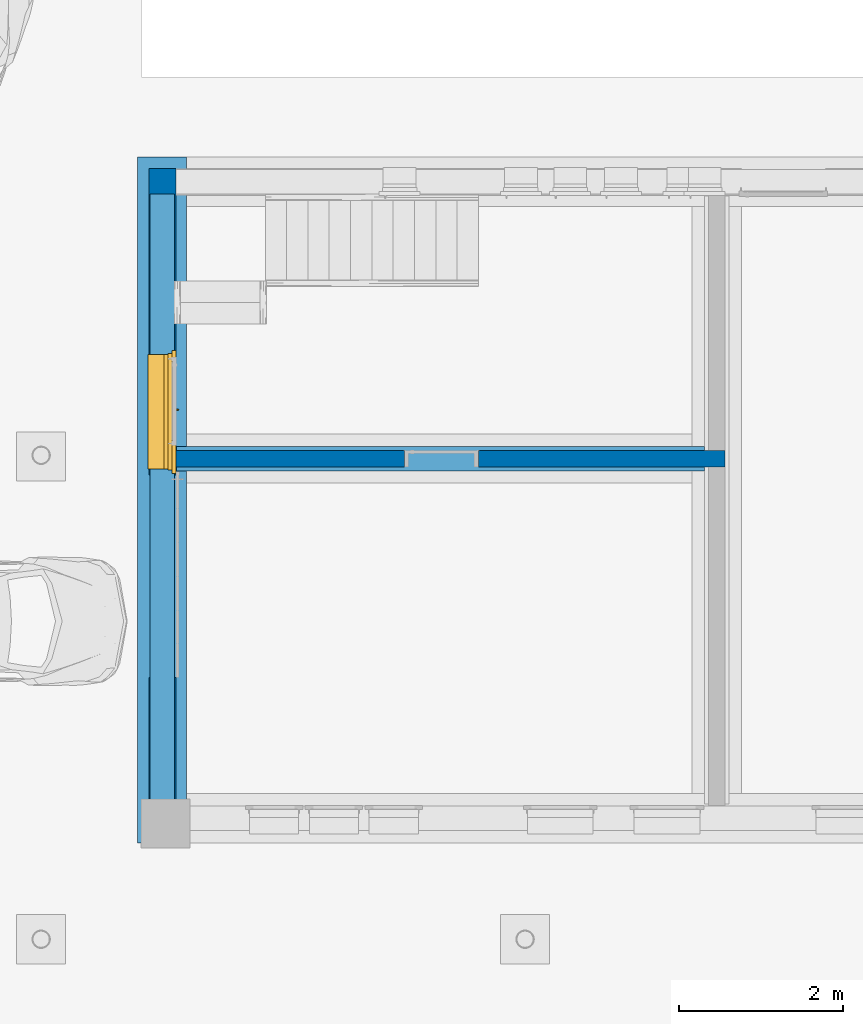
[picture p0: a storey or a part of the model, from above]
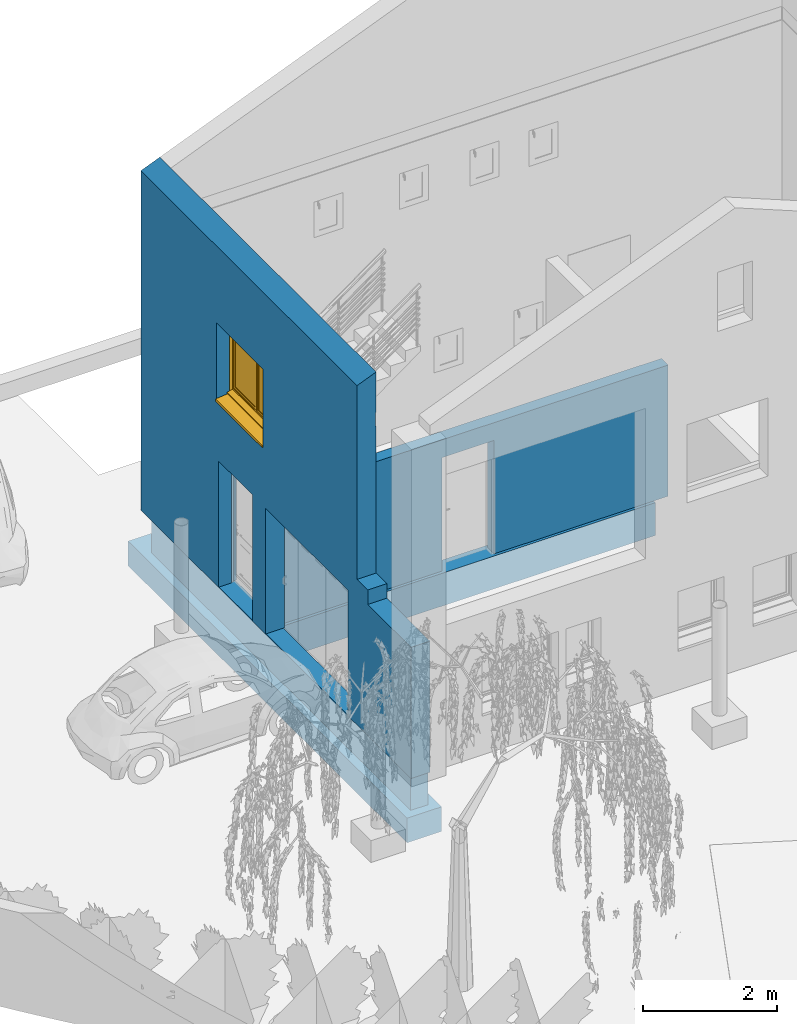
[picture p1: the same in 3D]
Properties of the parts of a building model (IFC2X3)

# File
Description: ViewDefinition [CoordinationView_V2.0, QuantityTakeOffAddOnView]
File name: Numéro du projet
Time: 2022-11-21T19:39:14
Written by: The EXPRESS Data Manager Version 5.02.0100.07 : 28 Aug 2013
Made in: 22.0.2.392 - Exporter 22.0.2.392 - Interface utilisateur alternative 22.0.2.392
Comment: STEP Physical File produced by: The EXPRESS Data Manager Version 5.02.0100.07 : 28 Aug 2013 * Module: EDMstepFileFactory/EDMstandAlone * Creation date: Mon Nov 21 19:39:14 2022 * Host: DESKTOP-0GH62VQ * Database: C:\Users\PC-PAT~1\AppData\Local\Temp\c2ba28db-b95e-4a9b-a4a2-2ccf43ad36bc\0f3ee18b-cbed-4b06-b284-a12b78713adf\ifc * Database version: 5507 * Database creation date: Mon Nov 21 19:39:06 2022 * Schema: IFC2X3 * Model: DataRepository.ifc * Model creation date: Mon Nov 21 19:39:07 2022 * Header model: DataRepository.ifc_HeaderModel * Header model creation date: Mon Nov 21 19:39:07 2022 * EDMuser: sdai-user * EDMgroup: sdai-group * License ID and type: 5605 : Permanent license. Expiry date: * EDMstepFileFactory options: 020000

# IfcProject, Numéro du projet
LongName: Nom du projet; Phase: Etat du projet

# IfcSite, Surface:269051
RefLatitude: 48, 51, 23, 999633; RefLongitude: 2, 21, 3, 553905; RefElevation: 0 m

# IfcSite: Boîte à lettres - Personnelle:26 x 33 x 38.5, Boîte à lettres - Personnelle:26 x 33 x 38.5:391761
Material: Métal - Chrome, Polycarbonate - Clair, Métal - Alu brossé, Aluminium laqué - Gris

# IfcSite: Portail métal - Double:3000mm x 1100mm 2, Portail métal - Double:3000mm x 1100mm 2:387421
Material: Peinture - Or, Portail - Chapeaux piliers, Peinture - Noir, Portail - Couleur, Portail - Piliers

# IfcBuilding
Pset_BuildingCommon - NumberOfStoreys: 3

# IfcBuildingStorey: Niveau:Ligne du Niveau (3)
Name | LongName | Elevation (m)
Niveau rdc | Niveau rdc | -1.94916e-14
Niveau étage | Niveau étage | 2.65
Niveau comble | Niveau comble | 5.6

# IfcSpace: Ch1 3:344937, 3
In: Niveau étage
LongName: Ch1; InteriorOrExteriorSpace: INTERNAL
Pset_SpaceCommon - Reference: Ch1 3
BaseQuantities - NetFloorArea: 9.82818 m2; Height: 2.4384 m; GrossPerimeter: 12.88 m; GrossFloorArea: 9.82818 m2; GrossVolume: 23.965 m3

# IfcSpace: Ch2 7:344949, 7
In: Niveau étage
LongName: Ch2; InteriorOrExteriorSpace: INTERNAL
Pset_SpaceCommon - Reference: Ch2 7
BaseQuantities - NetFloorArea: 11.398 m2; Height: 2.4384 m; GrossPerimeter: 13.51 m; GrossFloorArea: 11.398 m2; GrossVolume: 27.7929 m3

# IfcSpace: Cuisine 6:344946, 6
In: Niveau étage
LongName: Cuisine; InteriorOrExteriorSpace: INTERNAL
Pset_SpaceCommon - Reference: Cuisine 6
BaseQuantities - NetFloorArea: 9.671 m2; Height: 2.4384 m; GrossPerimeter: 12.46 m; GrossFloorArea: 9.671 m2; GrossVolume: 23.5818 m3

# IfcSpace: Dgt 4:344940, 4
In: Niveau étage
LongName: Dgt; InteriorOrExteriorSpace: INTERNAL
Pset_SpaceCommon - Reference: Dgt 4
BaseQuantities - NetFloorArea: 8.32768 m2; Height: 2.4384 m; GrossPerimeter: 13.481 m; GrossFloorArea: 8.32768 m2; GrossVolume: 20.3062 m3

# IfcSpace: Entrée 16:398265, 16
In: Niveau rdc
LongName: Entrée; InteriorOrExteriorSpace: INTERNAL
Pset_SpaceCommon - Reference: Entrée 16
BaseQuantities - NetFloorArea: 20.1594 m2; Height: 2.4384 m; GrossPerimeter: 19.1951 m; GrossFloorArea: 20.1594 m2; GrossVolume: 49.1568 m3

# IfcSpace: Garage 8:344957, 8
In: Niveau rdc
LongName: Garage; InteriorOrExteriorSpace: INTERNAL
Pset_SpaceCommon - Reference: Garage 8
BaseQuantities - NetFloorArea: 26.8007 m2; Height: 2.4384 m; GrossPerimeter: 21.2451 m; GrossFloorArea: 26.8007 m2; GrossVolume: 65.3509 m3

# IfcSpace: Pièce 10:345585, 10
In: Niveau comble
LongName: Pièce; InteriorOrExteriorSpace: INTERNAL
Pset_SpaceCommon - Reference: Pièce 10
BaseQuantities - NetFloorArea: 16.624 m2; Height: 2.4384 m; GrossPerimeter: 16.7226 m; GrossFloorArea: 16.624 m2; GrossVolume: 40.5359 m3

# IfcSpace: Pièce 9:345581, 9
In: Niveau comble
LongName: Pièce; InteriorOrExteriorSpace: INTERNAL
Pset_SpaceCommon - Reference: Pièce 9
BaseQuantities - NetFloorArea: 17.0934 m2; Height: 2.4384 m; GrossPerimeter: 16.69 m; GrossFloorArea: 17.0934 m2; GrossVolume: 41.6804 m3

# IfcSpace: Salon 5:344943, 5
In: Niveau étage
LongName: Salon; InteriorOrExteriorSpace: INTERNAL
Pset_SpaceCommon - Reference: Salon 5
BaseQuantities - NetFloorArea: 24.1371 m2; Height: 2.4384 m; GrossPerimeter: 28.9033 m; GrossFloorArea: 24.1371 m2; GrossVolume: 58.856 m3

# IfcSpace: SdB 1:344931, 1
In: Niveau étage
LongName: SdB; InteriorOrExteriorSpace: INTERNAL
Pset_SpaceCommon - Reference: SdB 1
BaseQuantities - NetFloorArea: 3.70925 m2; Height: 2.4384 m; GrossPerimeter: 7.71 m; GrossFloorArea: 3.70925 m2; GrossVolume: 9.04464 m3

# IfcSpace: Studio 15:396011, 15
In: Niveau rdc
LongName: Studio; InteriorOrExteriorSpace: INTERNAL
Pset_SpaceCommon - Reference: Studio 15
BaseQuantities - NetFloorArea: 28.8287 m2; Height: 2.4384 m; GrossPerimeter: 22.6249 m; GrossFloorArea: 28.8287 m2; GrossVolume: 70.2958 m3

# IfcSpace: Wc 2:344934, 2
In: Niveau étage
LongName: Wc; InteriorOrExteriorSpace: INTERNAL
Pset_SpaceCommon - Reference: Wc 2
BaseQuantities - NetFloorArea: 1.90475 m2; Height: 2.4384 m; GrossPerimeter: 5.91 m; GrossFloorArea: 1.90475 m2; GrossVolume: 4.64454 m3

# IfcBeam: IPE-Poutrelles:IPE200 (2)
In: Niveau étage
Type - Pset_BeamCommon - IsExternal: no; LoadBearing: yes
Material: Métal - Acier - 345 MPa
BaseQuantities - GrossSurfaceArea: 0 m2
Pset_BeamCommon - Reference: IPE200
Pset_QuantityTakeOff - Reference: IPE200; sets with these values: 2
Name (IPE-Poutrelles:IPE200:...) | NetVolume (m3) | Slope (deg) | Span (m) | NetSurfaceArea (m2)
289930 | 0.0223025 | 0 | 8.185 | 6.29341
290069 | 0.0241417 | 0.51735 | 8.86 | 6.81194

# IfcBeam: IPE-Poutrelles:IPE80 (29)
In: Niveau étage
Type - Pset_BeamCommon - IsExternal: no; LoadBearing: yes
BaseQuantities - GrossSurfaceArea: 0 m2
Pset_BeamCommon - Reference: IPE80; Slope: 0 deg
Pset_QuantityTakeOff - Reference: IPE80; sets with these values: 2
Name (IPE-Poutrelles:IPE80:...) | Material | NetVolume (m3) | Span (m) | NetSurfaceArea (m2)
288680 | Métal - Acier - 345 MPa | 0.00150805 | 2.03 | 0.666997
288683 | Métal - Acier - 345 MPa | 0.00150805 | 2.03 | 0.666997
288686 | Métal - Acier - 345 MPa | 0.00150805 | 2.03 | 0.666997
288689 | Métal - Acier - 345 MPa | 0.00150805 | 2.03 | 0.666997
288692 | Métal - Acier - 345 MPa | 0.00150805 | 2.03 | 0.666997
288695 | Métal - Acier - 345 MPa | 0.00150805 | 2.03 | 0.666997
288698 | Métal - Acier - 345 MPa | 0.00150805 | 2.03 | 0.666997
288701 | Métal - Acier - 345 MPa | 0.00150805 | 2.03 | 0.666997
288704 | Métal - Acier - 345 MPa | 0.00150805 | 2.03 | 0.666997
288707 | Métal - Acier - 345 MPa | 0.00150805 | 2.03 | 0.666997
288710 | Métal - Acier - 345 MPa | 0.00140924 | 1.91 | 0.623397
288713 | Métal - Acier - 345 MPa | 0.00114552 | 1.61 | 0.507021
288716 | Métal - Acier - 345 MPa | 0.000719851 | 1.037 | 0.319184
290215 | Peinture - Noir | 0.00142262 | 1.915 | 0.629298
290218 | Métal - Acier - 345 MPa | 0.00142262 | 1.915 | 0.629298
290221 | Métal - Acier - 345 MPa | 0.00142262 | 1.915 | 0.629298
290224 | Métal - Acier - 345 MPa | 0.00142262 | 1.915 | 0.629298
290227 | Métal - Acier - 345 MPa | 0.00142262 | 1.915 | 0.629298
290230 | Métal - Acier - 345 MPa | 0.00142262 | 1.915 | 0.629298
290233 | Métal - Acier - 345 MPa | 0.00142262 | 1.915 | 0.629298
290236 | Métal - Acier - 345 MPa | 0.00142262 | 1.915 | 0.629298
290239 | Métal - Acier - 345 MPa | 0.00142262 | 1.915 | 0.629298
290242 | Métal - Acier - 345 MPa | 0.00142262 | 1.915 | 0.629298
290245 | Métal - Acier - 345 MPa | 0.00133496 | 1.915 | 0.590616
363687 | Métal - Acier - 345 MPa | 0.00133496 | 1.812 | 0.590616
363748 | Métal - Acier - 345 MPa | 0.000941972 | 1.337 | 0.417199
364011 | Métal - Acier - 345 MPa | 0.001982 | 2.704 | 0.876142
364347 | Métal - Acier - 345 MPa | 0.000514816 | 0.762 | 0.228707
364498 | Peinture - Noir | 0.00134461 | 1.81 | 0.594876

# IfcBuildingElementProxy: Arbre 3D - Saule pleureur:Saule pleureur - 6 m, Arbre 3D - Saule pleureur:Saule pleureur - 6 m:264246
In: Niveau rdc
Type - Material: <Unnamed>
Pset_BuildingElementProxyCommon - Reference: Saule pleureur - 6 m; sets with these values: 2

# IfcBuildingElementProxy: Kitchenette - Moyenne:1372 mm, Kitchenette - Moyenne:1372 mm:354255
In: 6
Type - Material: Bois - Mélaminé blanc, Plastique - Noir, Métal - Chrome
Material: Métal - Chrome, Métal - Acier, Poli, <Unnamed>, Métal - Finition peinture - Ivoire, Mat, Peinture - Ivoire, Plastique - Noir, Bois - Mélaminé blanc, Bois - Mélaminé hêtre
Pset_BuildingElementProxyCommon - Reference: 1372 mm; sets with these values: 2

# IfcBuildingElementProxy: Meuble TV:1470 x 500 x 560 mm, Meuble TV:1470 x 500 x 560 mm:340517
In: Niveau comble
Type - Material: Bois - Mélaminé rouge, Verre - Meuble TV
Material: Verre - Meuble TV, Bois - Mélaminé rouge, Bois - Mélaminé gris
Pset_BuildingElementProxyCommon - Reference: 1470 x 500 x 560 mm; sets with these values: 2

# IfcBuildingElementProxy: Meuble TV:Meuble TV, Meuble TV:Meuble TV:354305
In: 5
Type - Material: Bois - Mélaminé rouge, Verre - Meuble TV
Material: Verre - Meuble TV, Bois - Mélaminé rouge, Bois - Mélaminé gris
Pset_BuildingElementProxyCommon - Reference: Meuble TV; sets with these values: 2

# IfcBuildingElementProxy: RPC Arbre - Feuilles caduques:Cerisier japonais - 4.5 mètres, RPC Arbre - Feuilles caduques:Cerisier japonais - 4.5 mètres:331745
In: Niveau comble
Type - Material: <Unnamed>
Pset_BuildingElementProxyCommon - Reference: Cerisier japonais - 4.5 mètres; sets with these values: 2

# IfcBuildingElementProxy: RPC Arbuste:Laurier-rose - 1.62 mètres (21)
In: Niveau rdc
Type - Material: <Unnamed>
Pset_BuildingElementProxyCommon - Reference: Laurier-rose - 1.62 mètres; sets with these values: 2
Name (RPC Arbuste:Laurier-rose - 1.62 mètres:...)
265842
265873
265898
265975
266002
266037
266072
266119
266152
266185
266230
266255
266351
266424
266471
266728
266797
266842
266947
266998
267203

# IfcBuildingElementProxy: RPC Coccinelle:RPC Coccinelle (3)
In: Niveau rdc
Type - Material: <Unnamed>
Pset_BuildingElementProxyCommon - Reference: RPC Coccinelle; sets with these values: 2
Name (RPC Coccinelle:RPC Coccinelle:...)
281773
281916
282133

# IfcBuildingElementProxy: RPC Femme:Lisa, RPC Femme:Lisa:361304
In: Niveau étage
Type - Material: <Unnamed>
Pset_BuildingElementProxyCommon - Reference: Lisa; sets with these values: 2

# IfcBuildingElementProxy: TV - Ecran plat:810 mm, TV - Ecran plat:810 mm:355405
In: 5
Type - Material: TV - Cadre
Material: TV - Cadre, TV - Noir, TV - Verre
Pset_BuildingElementProxyCommon - Reference: 810 mm; sets with these values: 2

# IfcColumn: Poteau béton - Carré:600mm x 600mm (4)
In: Niveau rdc
Type - PredefinedType: COLUMN; Material: Maçonnerie - Béton coulé sur place
Type - Pset_ColumnCommon - IsExternal: no; LoadBearing: yes
BaseQuantities - CrossSectionArea: 0.36 m2
Pset_ColumnCommon - Reference: 600mm x 600mm
Pset_QuantityTakeOff - Reference: 600mm x 600mm; sets with these values: 2
Name (Poteau béton - Carré:600mm x 600mm:...) | Length (m) | OuterSurfaceArea (m2) | GrossVolume (m3) = NetVolume (m3)
238808 | 6.16673 | 14.8002 | 2.22002
286273 | 0.4 | 0.96 | 0.144
286579 | 0.4 | 0.96 | 0.144
290105 | 0.4 | 0.96 | 0.144

# IfcColumn: Profil creux circulaire PCC:219.1x8CHS, Profil creux circulaire PCC:219.1x8CHS:316609
In: Niveau étage
Type - PredefinedType: COLUMN; Material: Métal - Acier
Type - Pset_ColumnCommon - IsExternal: no; LoadBearing: yes
BaseQuantities - Length: 5.95 m; CrossSectionArea: 0.00530481 m2; OuterSurfaceArea: 7.89196 m2; GrossVolume: 0.0315636 m3; NetVolume: 0.0315734 m3
Pset_ColumnCommon - Reference: 219.1x8CHS
Pset_QuantityTakeOff - Reference: 219.1x8CHS; sets with these values: 2

# IfcColumn: Profil creux circulaire PCC:219.1x8CHS (3)
In: Niveau rdc
Type - PredefinedType: COLUMN; Material: Peinture - Noir
Type - Pset_ColumnCommon - IsExternal: no; LoadBearing: yes
BaseQuantities - Length: 1.97 m; CrossSectionArea: 0.00530481 m2; OuterSurfaceArea: 2.61297 m2; GrossVolume: 0.0104505 m3; NetVolume: 0.0104537 m3
Pset_ColumnCommon - Reference: 219.1x8CHS
Pset_QuantityTakeOff - Reference: 219.1x8CHS; sets with these values: 2
Name (Profil creux circulaire PCC:219.1x8CHS:...)
287799
287893
290107

# IfcDoor: Entrée (avec angle d'ouverture):PP Avec moulures (0.90 m x 2.15 m), Entrée (avec angle d'ouverture):PP Avec moulures (0.90 m x 2.15 m):258819
In: Niveau rdc
Type - OperationType: SINGLE_SWING_LEFT; ParameterTakesPrecedence: no; Sizeable: no; Material: Porte d'entrée - Poignée, Porte d'entrée - Panneau, Peinture - Noir, Porte d'entrée - Cadre
Type - Entrée (avec angle d'ouverture):PP Avec moulures (0.90 m x 2.15 m):258819:1 - PanelOperation: SWINGING
Type - Pset_DoorCommon - IsExternal: yes; ThermalTransmittance: 5.5617 kg/K/s3
OverallHeight: 2.34 m; OverallWidth: 1.08 m; Material: Porte d'entrée - Poignée, Porte d'entrée - Panneau, Porte d'entrée - Cadre
Pset_DoorCommon - Reference: PP Avec moulures (0.90 m x 2.15 m)
Pset_QuantityTakeOff - Reference: PP Avec moulures (0.90 m x 2.15 m)
BaseQuantities - Height: 2.3 m; Width: 1 m; Area: 2.3 m2

# IfcDoor: Entrée (avec angle d'ouverture):PP Avec moulures (0.90 m x 2.15 m), Entrée (avec angle d'ouverture):PP Avec moulures (0.90 m x 2.15 m):302061
In: Niveau rdc
Type - OperationType: SINGLE_SWING_RIGHT; ParameterTakesPrecedence: no; Sizeable: no; Material: Porte d'entrée - Poignée, Porte d'entrée - Panneau, Porte d'entrée - Cadre, Peinture - Noir
Type - Entrée (avec angle d'ouverture):PP Avec moulures (0.90 m x 2.15 m):302061:1 - PanelOperation: SWINGING
Type - Pset_DoorCommon - IsExternal: yes; ThermalTransmittance: 5.5617 kg/K/s3
OverallHeight: 2.34 m; OverallWidth: 1.08 m; Material: Porte d'entrée - Poignée, Porte d'entrée - Panneau, Porte d'entrée - Cadre
Pset_DoorCommon - Reference: PP Avec moulures (0.90 m x 2.15 m)
Pset_QuantityTakeOff - Reference: PP Avec moulures (0.90 m x 2.15 m)
BaseQuantities - Height: 2.3 m; Width: 1 m; Area: 2.3 m2

# IfcDoor: Garage coulissante:Garage coulissante, Garage coulissante:Garage coulissante:237741
In: Niveau rdc
Type - OperationType: SLIDING_TO_LEFT; ParameterTakesPrecedence: no; Sizeable: no; Material: Peinture - Grise, Plastique - Noir
Type - Garage coulissante:Garage coulissante:237741:1 - PanelOperation: SLIDING
Type - Pset_DoorCommon - IsExternal: yes; ThermalTransmittance: 3.7021 kg/K/s3
OverallHeight: 2.3 m; OverallWidth: 2.47 m; Material: Peinture - Grise, Verre, Plastique - Noir
Pset_DoorCommon - Reference: Garage coulissante
Pset_QuantityTakeOff - Reference: Garage coulissante
BaseQuantities - Height: 2.3 m; Width: 2.47 m; Area: 5.681 m2

# IfcDoor: Int. Double vitrée:Cintré 2x4 - 1.46 m x 2.04 m, Int. Double vitrée:Cintré 2x4 - 1.46 m x 2.04 m:275557
In: Niveau étage
Type - OperationType: DOUBLE_DOOR_SINGLE_SWING; ParameterTakesPrecedence: no; Sizeable: no; Material: Porte - Poignée, Porte - Panneau, Porte - Cadre, Verre
Type - Int. Double vitrée:Cintré 2x4 - 1.46 m x 2.04 m:275557:1 - PanelOperation: SWINGING
Type - Pset_DoorCommon - IsExternal: no; ThermalTransmittance: 3.6886 kg/K/s3
OverallHeight: 2.075 m; OverallWidth: 1.53 m; Material: Verre, Porte - Panneau, Porte - Poignée, Porte - Cadre
Pset_DoorCommon - Reference: Cintré 2x4 - 1.46 m x 2.04 m
Pset_QuantityTakeOff - Reference: Cintré 2x4 - 1.46 m x 2.04 m
BaseQuantities - Height: 2.04 m; Width: 1.46 m; Area: 2.9784 m2

# IfcDoor: Int. Simple:PP (0.73m x 2.04m) (3)
In: Niveau étage
Type - ParameterTakesPrecedence: no; Sizeable: no; Material: Bois - Cadre de porte, Bois - Panneau de porte, Finition Peinture - Blanc satiné
Type - Pset_DoorCommon - IsExternal: no; ThermalTransmittance: 3.7021 kg/K/s3
OverallHeight: 2.075 m; OverallWidth: 0.8 m; Material: Finition Peinture - Blanc satiné, Bois - Panneau de porte, Bois - Cadre de porte
Pset_DoorCommon - Reference: PP (0.73m x 2.04m)
Pset_QuantityTakeOff - Reference: PP (0.73m x 2.04m)
BaseQuantities - Height: 2.04 m; Width: 0.73 m; Area: 1.4892 m2
Name (Int. Simple:PP (0.73m x 2.04m):...)
261310
284174
284381

# IfcDoor: Int. Simple:PP (0.73m x 2.04m) (4)
In: Niveau comble
Type - ParameterTakesPrecedence: no; Sizeable: no; Material: Bois - Panneau de porte, Finition Peinture - Blanc satiné, Bois - Cadre de porte
Type - Pset_DoorCommon - IsExternal: no; ThermalTransmittance: 3.7021 kg/K/s3
OverallHeight: 2.075 m; OverallWidth: 0.8 m; Material: Finition Peinture - Blanc satiné, Bois - Panneau de porte, Bois - Cadre de porte
Pset_DoorCommon - Reference: PP (0.73m x 2.04m)
Pset_QuantityTakeOff - Reference: PP (0.73m x 2.04m)
BaseQuantities - Height: 2.04 m; Width: 0.73 m; Area: 1.4892 m2
Name (Int. Simple:PP (0.73m x 2.04m):...)
331886
356352
356991
357021

# IfcDoor: Int. Simple:PP (0.73m x 2.04m), Int. Simple:PP (0.73m x 2.04m):284512
In: Niveau étage
Type - ParameterTakesPrecedence: no; Sizeable: no; Material: Finition Peinture - Blanc satiné, Bois - Cadre de porte, Bois - Panneau de porte
Type - Pset_DoorCommon - IsExternal: no; ThermalTransmittance: 3.7021 kg/K/s3
OverallHeight: 2.075 m; OverallWidth: 0.8 m; Material: Finition Peinture - Blanc satiné, Bois - Panneau de porte, Bois - Cadre de porte
Pset_DoorCommon - Reference: PP (0.73m x 2.04m)
Pset_QuantityTakeOff - Reference: PP (0.73m x 2.04m)
BaseQuantities - Height: 2.04 m; Width: 0.73 m; Area: 1.4892 m2

# IfcDoor: Int. Simple:PP (0.73m x 2.04m) (2)
In: Niveau étage
Type - ParameterTakesPrecedence: no; Sizeable: no; Material: Finition Peinture - Blanc satiné, Bois - Panneau de porte, Bois - Cadre de porte
Type - Pset_DoorCommon - IsExternal: no; ThermalTransmittance: 3.7021 kg/K/s3
OverallHeight: 2.075 m; OverallWidth: 0.8 m
Pset_DoorCommon - Reference: PP (0.73m x 2.04m)
Pset_QuantityTakeOff - Reference: PP (0.73m x 2.04m)
BaseQuantities - Height: 2.04 m; Width: 0.73 m; Area: 1.4892 m2
Name (Int. Simple:PP (0.73m x 2.04m):...)
284363
284456

# IfcDoor: Int. Simple:PP (0.83m x 2.04m), Int. Simple:PP (0.83m x 2.04m):395213
In: Niveau rdc
Type - ParameterTakesPrecedence: no; Sizeable: no; Material: Finition Peinture - Blanc satiné, Bois - Cadre de porte, Bois - Panneau de porte
Type - Pset_DoorCommon - IsExternal: no; ThermalTransmittance: 3.7021 kg/K/s3
OverallHeight: 2.075 m; OverallWidth: 0.9 m; Material: Finition Peinture - Blanc satiné, Bois - Panneau de porte, Bois - Cadre de porte
Pset_DoorCommon - Reference: PP (0.83m x 2.04m)
Pset_QuantityTakeOff - Reference: PP (0.83m x 2.04m)
BaseQuantities - Height: 2.04 m; Width: 0.83 m; Area: 1.6932 m2

# IfcDoor: Ouverture en rectangle:Ouverture en rectangle, Ouverture en rectangle:Ouverture en rectangle:277625
In: Niveau comble
Type - ParameterTakesPrecedence: no; Sizeable: no; Material: Bois - Chêne
Type - Pset_DoorCommon - IsExternal: no
OverallHeight: 2.1 m; OverallWidth: 0.9 m
Pset_DoorCommon - Reference: Ouverture en rectangle
Pset_QuantityTakeOff - Reference: Ouverture en rectangle
BaseQuantities - Height: 2.1 m; Width: 0.9 m; Area: 1.89 m2

# IfcElementAssembly: Réseau de poutres:Système de poutre - Intervalle fixe 2 m (2)
In: Niveau étage
PredefinedType: BEAM_GRID
Pset_QuantityTakeOff - Reference: Système de poutre - Intervalle fixe 2 m
Name (Réseau de poutres:Système de poutre - Intervalle fixe 2 m:...)
288171
290139

# IfcFlowTerminal: Baignoire:1830 x 915mm, Baignoire:1830 x 915mm:336773
In: Niveau comble
Type - Material: Plastique - Blanc, Porcelaine - Blanche
Material: Porcelaine - Blanche
Pset_DistributionFlowElementCommon - Reference: 1830 x 915mm; sets with these values: 2

# IfcFlowTerminal: Cuvette réservoir:Cuvette réservoir (2)
Type - Material: Porcelaine - Lin (2)
Pset_DistributionFlowElementCommon - Reference: Cuvette réservoir; sets with these values: 2
Name (Cuvette réservoir:Cuvette réservoir:...) | In
344000 | Niveau comble
349442 | 2 | Material: Porcelaine - Lin, Stratifié - Lin, Mat

# IfcFlowTerminal: Lavabo moderne:Lavabo moderne, Lavabo moderne:Lavabo moderne:335771
In: Niveau comble
Type - Material: Métal - Chrome poli, Bois - Noyer naturel, Porcelaine - Blanche
Material: Métal - Chrome poli, Porcelaine - Blanche, Bois - Noyer naturel
Pset_DistributionFlowElementCommon - Reference: Lavabo moderne; sets with these values: 2

# IfcFurnishingElement: Canapé 2 places:180 x 88 x 66 cm - Noir, Canapé 2 places:180 x 88 x 66 cm - Noir:350356
In: 5
Type - Material: Plastique - Noir, Tissu - Noir
Material: Tissu - Noir, Plastique - Noir
Pset_QuantityTakeOff - Reference: 180 x 88 x 66 cm - Noir

# IfcFurnishingElement: Fauteuil de relaxation:Fauteuil de relaxation (2)
In: Niveau comble
Type - Material: Textile - Tissu bleu (2), Bois - Hêtre (16)
Pset_QuantityTakeOff - Reference: Fauteuil de relaxation
Name (Fauteuil de relaxation:Fauteuil de relaxation:...)
341898
342254 | Material: Textile - Tissu bleu, Bois - Hêtre

# IfcFurnishingElement: Lit - Type 01:2100 x 1400 x 800 mm (4)
Type - Material: Métal - Aluminium, Aggloméré - Blanc, Aggloméré - Gris, Tissus - Lin beige
Material: Aggloméré - Blanc, Tissus - Lin beige, Aggloméré - Gris, Métal - Aluminium, Plastique - Noir
Pset_QuantityTakeOff - Reference: 2100 x 1400 x 800 mm
Name (Lit - Type 01:2100 x 1400 x 800 mm:...) | In
333700 | 10
334156 | 9
349883 | 3
350012 | 7

# IfcOpeningElement: Opening (36)
Name | In | Depth (m) | Height (m) | Width (m)
Mur de base:bloc monomur30:236646:1 | Niveau rdc | Pset_ManufacturerTypeInformation - Manufacturer: wienerberger; Pset_OpeningElementCommon - Reference: bloc monomur30; sets with these values: 2
Mur de base:bloc monomur30:236742:1 | Niveau rdc | Pset_ManufacturerTypeInformation - Manufacturer: wienerberger; Pset_OpeningElementCommon - Reference: bloc monomur30; sets with these values: 2
Sol:Dalle en béton - 250 mm:236820:2 | Niveau étage | 0.25 | 2.64258 | 1.07452 | Pset_OpeningElementCommon - Reference: Dalle en béton - 250 mm; sets with these values: 2
Mur de base:Int. Plâtre 7cm:29322 | Niveau étage | Pset_OpeningElementCommon - Reference: Int. Plâtre 7cm; sets with these values: 2; BaseQuantities - Area: 5.11427 m2
Mur de base:Int. Plâtre 7cm:261247 | Niveau étage | 0.8 | 2.075 | 0.07 | Pset_OpeningElementCommon - Reference: PP (0.73m x 2.04m); sets with these values: 2
Sol:Dalle en béton - 250 mm:283429:2 | Niveau comble | 0.25 | 1.15067 | 3.39537 | Pset_OpeningElementCommon - Reference: Dalle en béton - 250 mm; sets with these values: 2
Sol:plancher bois:290382:2 | Niveau étage | 0.025 | 0.6 | 0.6 | Pset_OpeningElementCommon - Reference: plancher bois; sets with these values: 2
Int. Simple:PP (0.83m x 2.04m):395213:1 | Niveau rdc | 0.2 | 0.9 | 2.075
Mur de base:Ext. Voile 30:373991 | Niveau rdc | Pset_OpeningElementCommon - Reference: PP Avec moulures (0.90 m x 2.15 m); sets with these values: 2
Mur de base:Ext. Voile 30:374069 | Niveau rdc | Pset_OpeningElementCommon - Reference: PP Avec moulures (0.90 m x 2.15 m); sets with these values: 2
Mur de base:Ext. Voile 30:374069 | Niveau rdc | 3.048 | 2.3 | 2.47 | Pset_OpeningElementCommon - Reference: Garage coulissante; sets with these values: 2
Int. Simple:PP (0.73m x 2.04m):357021:1 | Niveau comble | 0.07 | 0.8 | 2.075
2 x Mur de base:bloc monomur30:236646 | Niveau rdc
Garage coulissante:Garage coulissante:237741:1 | Niveau rdc | 0.33 | 2.47 | 2.3
2 x Mur de base:bloc monomur30:236742 | Niveau rdc
7 x Mur de base:bloc monomur30:236793 | Niveau rdc
Mur de base:Ext. Parpaing 35:238144 | Niveau étage
Int. Simple:PP (0.73m x 2.04m):261310:1 | Niveau étage | 0.07 | 0.8 | 2.075
Int. Simple:PP (0.73m x 2.04m):284174:1 | Niveau étage | 0.2 | 0.8 | 2.075
Int. Simple:PP (0.73m x 2.04m):284512:1 | Niveau étage | 0.2 | 0.8 | 2.075
Int. Double vitrée:Cintré 2x4 - 1.46 m x 2.04 m:275557:1 | Niveau étage | 0.07 | 1.53 | 2.075
Int. Simple:PP (0.73m x 2.04m):284363:1 | Niveau étage | 0.07 | 0.8 | 2.075
Int. Simple:PP (0.73m x 2.04m):284381:1 | Niveau étage | 0.07 | 0.8 | 2.075
Int. Simple:PP (0.73m x 2.04m):284456:1 | Niveau étage | 0.07 | 0.8 | 2.075
Ouverture en rectangle:Ouverture en rectangle:277625:1 | Niveau comble | 0.2 | 0.9 | 2.1
Int. Simple:PP (0.73m x 2.04m):331886:1 | Niveau comble | 0.07 | 0.8 | 2.075
Int. Simple:PP (0.73m x 2.04m):356352:1 | Niveau comble | 0.07 | 0.8 | 2.075
Int. Simple:PP (0.73m x 2.04m):356991:1 | Niveau comble | 0.07 | 0.8 | 2.075

# IfcRailing: Garde-corps:Type Bateau (8)
Pset_QuantityTakeOff - Reference: Type Bateau
Pset_RailingCommon - IsExternal: no; Reference: Type Bateau; Height: 0.9 m
Name (Garde-corps:Type Bateau:...) | In | Length (m)
259351 | Niveau étage | 4.79638
291246 | Niveau étage | 10.3504
292406 | Niveau étage | 10.8
316494 | Niveau comble | 3.4 | Material: Peinture - Grise (5), Peinture - Noir (5), Plastique - Noir, Pin (1)
317755 | Niveau rdc | 0.643208
317759 | Niveau rdc | 0.643208
317763 | Niveau rdc | 3.21604
317767 | Niveau rdc | 3.21604

# IfcRoof: Toit de base:Toit - 200 mm, Toit de base:Toit - 200 mm:238331
In: Niveau comble
Material: Toit par défaut 0.2 m
Pset_QuantityTakeOff - Reference: Toit - 200 mm
Pset_RoofCommon - IsExternal: yes; Reference: Toit - 200 mm; ProjectedArea: 111.597 m2; TotalArea: 115.619 m2

# IfcRoof: Toit de base:isolation toiture, Toit de base:isolation toiture:365778
In: Niveau comble
Pset_QuantityTakeOff - Reference: isolation toiture
Pset_RoofCommon - IsExternal: yes; Reference: isolation toiture; ProjectedArea: 78.5879 m2; TotalArea: 84.7598 m2

# IfcSlab: Sol:Dalle en béton - 20, Sol:Dalle en béton - 20:377366:3
In: Niveau rdc
Type - PredefinedType: FLOOR; Material: Maçonnerie - Béton 0.2 m
Type - Pset_SlabCommon - IsExternal: no
Pset_QuantityTakeOff - Reference: Dalle en béton - 20; sets with these values: 2
Pset_SlabCommon - LoadBearing: no; PitchAngle: 0 deg; Reference: Dalle en béton - 20
BaseQuantities - GrossArea: 26.2857 m2; NetArea: 74.4247 m2; NetVolume: 14.8849 m3; Perimeter: 21.0451 m

# IfcSlab: Sol:Dalle en béton - 20 (2)
In: Niveau rdc
Type - PredefinedType: FLOOR
Type - Pset_SlabCommon - IsExternal: no
Material: Maçonnerie - Béton 0.2 m
Pset_QuantityTakeOff - Reference: Dalle en béton - 20; sets with these values: 2
Pset_SlabCommon - LoadBearing: no; PitchAngle: 0 deg; Reference: Dalle en béton - 20
BaseQuantities - NetArea: 74.4247 m2; NetVolume: 14.8849 m3
Name (Sol:Dalle en béton - 20:...) | GrossArea (m2) | Perimeter (m)
377366 | 19.6821 | 18.9951
377366:2 | 28.4569 | 22.5249

# IfcSlab: Sol:Dalle en béton - 250 mm (2)
Type - PredefinedType: FLOOR; Material: Maçonnerie - Béton 0.25 m
Type - Pset_SlabCommon - IsExternal: no
Pset_QuantityTakeOff - Reference: Dalle en béton - 250 mm; sets with these values: 2
Pset_SlabCommon - LoadBearing: no; Reference: Dalle en béton - 250 mm; PitchAngle: 0 deg
Name (Sol:Dalle en béton - 250 mm:...) | In | GrossArea (m2) | NetArea (m2) | NetVolume (m3) | Perimeter (m)
236820 | Niveau étage | 81.5577 | 78.7182 | 19.6795 | 37.351
283429 | Niveau comble | 80.295 | 76.388 | 19.097 | 36.35

# IfcSlab: Sol:piscine, Sol:piscine:297293
In: Niveau rdc
Type - PredefinedType: FLOOR; Material: eau 0.025 m
Type - Pset_SlabCommon - IsExternal: no
Pset_QuantityTakeOff - Reference: piscine; sets with these values: 2
Pset_SlabCommon - LoadBearing: no; PitchAngle: 0 deg; Reference: piscine
BaseQuantities - GrossArea: 32 m2; NetArea: 32 m2; GrossVolume: 0.8 m3; NetVolume: 0.8 m3; Perimeter: 24 m; Width: 0.025 m

# IfcSlab: Sol:plancher bois, Sol:plancher bois:290382
In: Niveau étage
Type - PredefinedType: FLOOR; Material: Pin 0.025 m
Type - Pset_SlabCommon - IsExternal: no; ThermalTransmittance: 4.8 kg/K/s3
Pset_QuantityTakeOff - Reference: plancher bois; sets with these values: 2
Pset_SlabCommon - LoadBearing: no; PitchAngle: 0 deg; Reference: plancher bois
BaseQuantities - GrossArea: 36.9913 m2; NetArea: 36.6313 m2; NetVolume: 0.915783 m3; Perimeter: 34.4035 m

# IfcSlab: Terre-plein:Terre-plein Béton - 300 mm, Terre-plein:Terre-plein Béton - 300 mm:361527
In: Niveau rdc
Type - PredefinedType: FLOOR; Material: Maçonnerie - Béton pavé 0.3 m
Type - Pset_SlabCommon - IsExternal: no
Pset_QuantityTakeOff - Reference: Terre-plein Béton - 300 mm; sets with these values: 2
Pset_SlabCommon - PitchAngle: 0 deg; Reference: Terre-plein Béton - 300 mm
BaseQuantities - NetArea: 294.578 m2; NetVolume: 88.3733 m3

# IfcSlab: Toit de base:isolation toiture (2)
In: Niveau comble
Type - PredefinedType: ROOF
Type - Pset_SlabCommon - IsExternal: yes
Material: Maçonnerie - Isolant 0.2 m
Pset_QuantityTakeOff - Reference: isolation toiture; sets with these values: 2
Pset_SlabCommon - Reference: isolation toiture; PitchAngle: 22 deg
BaseQuantities - GrossArea: 3.93722 m2; NetArea: 84.7598 m2; GrossVolume: 0.787445 m3; NetVolume: 16.952 m3; Perimeter: 26.2701 m; Width: 0.2 m

# IfcStair: Escalier coulé sur place:Monobloc (2)
Pset_QuantityTakeOff - Reference: Monobloc
Pset_StairCommon - IsExternal: no; Reference: Monobloc
Name (Escalier coulé sur place:Escalier:...) | In | NumberOfRiser | NumberOfTreads | RiserHeight (m) | TreadLength (m)
259242 | Niveau étage | 16 | 15 | 0.184375 | 0.26125 | ShapeType: STRAIGHT_RUN_STAIR
317581 | Niveau rdc | 14 | 12 | 0.189286 | 0.26

# IfcStairFlight: Volée monobloc:Profondeur de structure 80 mm (3)
Type - PredefinedType: STRAIGHT
Material: Maçonnerie - Béton
Pset_QuantityTakeOff - Reference: Profondeur de structure 80 mm
Pset_StairFlightCommon - Reference: Profondeur de structure 80 mm; NosingLength: 0 m
Name (Escalier coulé sur place:Escalier:...) | In | NumberOfRiser = Pset_StairFlightCommon, NumberOfRiser | NumberOfTreads = Pset_StairFlightCommon, NumberOfTreads | RiserHeight (m) | TreadLength (m) | Pset_StairFlightCommon, RiserHeight (m) | Pset_StairFlightCommon, TreadLength (m) = TreadLengthAtOffset (m) = TreadLengthAtInnerSide (m) | WalkingLineOffset (m) | NetVolume (m3) | Length (m)
259242 Run 1 | Niveau étage | 16 | 15 | 0.604905 | 0.857119 | 0.184375 | 0.26125 | 1.64042 | 0.738178 | 3.91875
317581 Run 1 | Niveau rdc | 3 | 2 | 0.621016 | 0.853018 | 0.189286 | 0.26 | 1.80446 | 0.10334 | 0.52
317581 Run 2 | Niveau rdc | 11 | 10 | 0.621016 | 0.853018 | 0.189286 | 0.26 | 1.80446 | 0.55369 | 2.6

# IfcWall: Mur de base:bloc monomur30, Mur de base:bloc monomur30:318819
In: Niveau rdc
Type - PredefinedType: STANDARD; Material: Maçonnerie - Isolant 0.015 m, Blocs briques monomur 0.3 m, Maçonnerie - Isolant 0.015 m
Type - Pset_ManufacturerTypeInformation - Manufacturer: wienerberger
Type - Pset_WallCommon - ThermalTransmittance: 4.33333 kg/K/s3; IsExternal: yes
Pset_QuantityTakeOff - Reference: bloc monomur30; sets with these values: 2
Pset_WallCommon - Reference: bloc monomur30; ExtendToStructure: yes; LoadBearing: no

# IfcWallStandardCase: Mur de base:Ext. Brique 22 (3)
In: Niveau rdc
Type - PredefinedType: STANDARD; Material: Brique, commune 0.2 m
Type - Pset_WallCommon - IsExternal: yes; ThermalTransmittance: 2.7 kg/K/s3
BaseQuantities - Height: 2.4 m; Width: 0.2 m
Pset_QuantityTakeOff - Reference: Ext. Brique 22; sets with these values: 2
Pset_WallCommon - LoadBearing: no; ExtendToStructure: no; Reference: Ext. Brique 22
Name (Mur de base:Ext. Brique 22:...) | Length (m) | GrossFootprintArea (m2) | GrossVolume (m3) = NetVolume (m3) | GrossSideArea (m2) = NetSideArea (m2)
393267 | 6.69257 | 1.33851 | 2.83894 | 14.1947
394525 | 3.105 | 0.621 | 1.4904 | 7.452
394641 | 4.13 | 0.826 | 1.9824 | 9.912

# IfcWallStandardCase: Mur de base:Ext. Parpaing 20 (5)
In: Niveau rdc
Type - PredefinedType: STANDARD; Material: Maçonnerie - Isolant 0.015 m, Blocs béton manufacturés 0.2 m, Maçonnerie - Isolant 0.015 m
Type - Pset_WallCommon - IsExternal: yes; ThermalTransmittance: 6.5 kg/K/s3
BaseQuantities - Width: 0.23 m
Pset_QuantityTakeOff - Reference: Ext. Parpaing 20; sets with these values: 2
Pset_WallCommon - LoadBearing: no; ExtendToStructure: no; Reference: Ext. Parpaing 20
Name (Mur de base:Ext. Parpaing 20:...) | Height (m) | Length (m) | GrossFootprintArea (m2) | GrossVolume (m3) | GrossSideArea (m2) | NetSideArea (m2) | NetVolume (m3)
262323 | 1.8 | 26.8245 | 6.15567 | 0.171087 | 0.743855 | 48.1081 | 11.0338
262568 | 0.3 | 26.1961 | 6.02051 | 1.80727 | 7.8577 | 7.8577 | 1.80615
262733 | 0.3 | 26.0375 | 5.98443 | 1.79658 | 7.81124 | 7.81124 | 1.79533
262772 | 1.8 | 6.2 | 1.426 | 2.5668 | 11.16 | 11.16 | 2.5668
280096 | 1.8 | 2.8131 | 0.607811 | 1.16462 | 5.06359 | 5.06359 | 1.09406

# IfcWallStandardCase: Mur de base:Ext. Parpaing 35 (2)
In: Niveau étage
Type - PredefinedType: STANDARD; Material: Maçonnerie - Isolant 0.03 m, Blocs béton manufacturés 0.3 m, Maçonnerie - Isolant 0.02 m
Type - Pset_WallCommon - IsExternal: yes; ThermalTransmittance: 4.33333 kg/K/s3
BaseQuantities - Height: 2.7 m; Width: 0.35 m
Pset_QuantityTakeOff - Reference: Ext. Parpaing 35; sets with these values: 2
Pset_WallCommon - ExtendToStructure: yes; LoadBearing: no; Reference: Ext. Parpaing 35
Name (Mur de base:Ext. Parpaing 35:...) | Length (m) | GrossFootprintArea (m2) | GrossVolume (m3) | GrossSideArea (m2) | NetSideArea (m2) | NetVolume (m3)
238084 | 1.63548 | 0.572417 | 1.54553 | 4.41579 | 4.41579 | 1.54553
238144 | 3.72842 | 1.30495 | 3.52336 | 10.0667 | 4.62079 | 1.61187

# IfcWallStandardCase: Mur de base:Ext. Voile 30 (6)
In: Niveau rdc
Type - PredefinedType: STANDARD; Material: Maçonnerie - Voile BA 0.3 m
Type - Pset_WallCommon - IsExternal: yes
BaseQuantities - Height: 0.6 m; Width: 0.3 m
Pset_QuantityTakeOff - Reference: Ext. Voile 30; sets with these values: 2
Pset_WallCommon - ExtendToStructure: no; Reference: Ext. Voile 30
Name (Mur de base:Ext. Voile 30:...) | Length (m) | GrossFootprintArea (m2) | GrossVolume (m3) = NetVolume (m3) | GrossSideArea (m2) = NetSideArea (m2) | LoadBearing
373399 | 8.11 | 2.433 | 1.4598 | 4.866 | yes
373991 | 10.905 | 3.2715 | 1.9629 | 6.543 | yes
374069 | 7.76 | 2.328 | 1.3968 | 4.656 | yes
374176 | 10.605 | 3.1815 | 1.9089 | 6.363 | yes
398404 | 6.43757 | 1.93127 | 1.15876 | 3.86254 | no
398529 | 7.41 | 2.223 | 1.3338 | 4.446 | no

# IfcWallStandardCase: Mur de base:Générique - Ext. 200 mm, Mur de base:Générique - Ext. 200 mm:268382
In: Niveau étage
Type - PredefinedType: STANDARD; Material: Mur par défaut 0.2 m
Type - Pset_WallCommon - IsExternal: yes
BaseQuantities - Height: 2.7 m; Length: 6.495 m; Width: 0.2 m; GrossFootprintArea: 1.299 m2; GrossVolume: 2.8433 m3; GrossSideArea: 14.2165 m2; NetSideArea: 14.2165 m2; NetVolume: 2.8433 m3
Pset_QuantityTakeOff - Reference: Générique - Ext. 200 mm; sets with these values: 2
Pset_WallCommon - ExtendToStructure: yes; LoadBearing: no; Reference: Générique - Ext. 200 mm

# IfcWallStandardCase: Mur de base:Générique - Int. 70 mm (8)
In: Niveau comble
Type - PredefinedType: STANDARD; Material: Mur par défaut 0.07 m
Type - Pset_WallCommon - IsExternal: no
BaseQuantities - Width: 0.07 m
Pset_QuantityTakeOff - Reference: Générique - Int. 70 mm; sets with these values: 2
Pset_WallCommon - ExtendToStructure: yes; LoadBearing: no; Reference: Générique - Int. 70 mm
Name (Mur de base:Générique - Int. 70 mm:...) | Height (m) | Length (m) | GrossFootprintArea (m2) | GrossVolume (m3) | GrossSideArea (m2) = NetSideArea (m2) | NetVolume (m3)
328276 | 2.67777 | 3.61 | 0.2527 | 0.560472 | 8.00674 | 0.556899
342434 | 2.65001 | 0.956295 | 0.0669406 | 0.164461 | 2.34945 | 0.164461
342499 | 2.29192 | 0.5 | 0.035 | 0.0802173 | 1.14596 | 0.0797224
345124 | 2.67829 | 3.605 | 0.25235 | 0.559667 | 7.99524 | 0.556098
356536 | 2.68181 | 1.49 | 0.1043 | 0.163513 | 2.33589 | 0.162038
356603 | 2.87372 | 0.958705 | 0.0671094 | 0.0701545 | 1.00221 | 0.0701545
356804 | 2.65353 | 2.16 | 0.1512 | 0.335237 | 4.7891 | 0.335237
356860 | 1.78083 | 3.605 | 0.25235 | 0.449392 | 6.41989 | 0.445824

# IfcWallStandardCase: Mur de base:Int. Plâtre 7cm (7)
In: Niveau étage
Type - PredefinedType: STANDARD; Material: Mur par défaut 0.07 m
Type - Pset_WallCommon - IsExternal: no
BaseQuantities - Width: 0.07 m
Pset_QuantityTakeOff - Reference: Int. Plâtre 7cm; sets with these values: 2
Pset_WallCommon - LoadBearing: no; Reference: Int. Plâtre 7cm
Name (Mur de base:Int. Plâtre 7cm:...) | Height (m) | Length (m) | GrossFootprintArea (m2) | GrossVolume (m3) | GrossSideArea (m2) = NetSideArea (m2) | NetVolume (m3) | ExtendToStructure
259653 | 2.725 | 4.64713 | 0.325299 | 0.422409 | 6.03441 | 0.422409 | no
261247 | 2.7 | 2.005 | 0.14035 | 0.368777 | 5.26825 | 0.368778 | yes
268430 | 2.7 | 3.28 | 0.2296 | 0.61992 | 8.856 | 0.61992 | yes
268514 | 2.7 | 4.645 | 0.32515 | 0.655629 | 9.36614 | 0.655629 | yes
275647 | 2.7 | 2.94 | 0.2058 | 0.32326 | 4.618 | 0.32326 | yes
275785 | 2.7 | 3.955 | 0.27685 | 0.631295 | 9.0185 | 0.631295 | yes
275873 | 2.7 | 2.005 | 0.14035 | 0.378945 | 5.4135 | 0.378945 | yes

# IfcWallStandardCase: Mur de base:Parpaing 20, Mur de base:Parpaing 20:276755
In: Niveau comble
Type - PredefinedType: STANDARD; Material: Blocs béton manufacturés 0.2 m
Type - Pset_WallCommon - IsExternal: yes; ThermalTransmittance: 6.5 kg/K/s3
BaseQuantities - Height: 2.87372 m; Length: 10.57 m; Width: 0.2 m; GrossFootprintArea: 2.114 m2; GrossVolume: 3.44005 m3; GrossSideArea: 17.2003 m2; NetSideArea: 17.2003 m2; NetVolume: 3.44005 m3
Pset_QuantityTakeOff - Reference: Parpaing 20; sets with these values: 2
Pset_WallCommon - ExtendToStructure: yes; LoadBearing: no; Reference: Parpaing 20

# IfcWallStandardCase: Mur de base:bloc monomur30 (3)
In: Niveau rdc
Type - PredefinedType: STANDARD; Material: Maçonnerie - Isolant 0.015 m, Blocs briques monomur 0.3 m, Maçonnerie - Isolant 0.015 m
Type - Pset_ManufacturerTypeInformation - Manufacturer: wienerberger
Type - Pset_WallCommon - ThermalTransmittance: 4.33333 kg/K/s3; IsExternal: yes
BaseQuantities - Width: 0.33 m
Pset_QuantityTakeOff - Reference: bloc monomur30; sets with these values: 2
Pset_WallCommon - Reference: bloc monomur30; ExtendToStructure: yes; LoadBearing: no
Name (Mur de base:bloc monomur30:...) | Height (m) | Length (m) | GrossFootprintArea (m2) | GrossVolume (m3) | GrossSideArea (m2) | NetSideArea (m2) | NetVolume (m3)
236646 | 6.33642 | 8.095 | 2.67135 | 16.9268 | 51.2933 | 46.743 | 15.5691
236742 | 6.34046 | 8.095 | 2.67135 | 11.9276 | 36.1441 | 34.1421 | 11.3693
236793 | 8.47372 | 10.57 | 3.4881 | 25.0556 | 75.9261 | 74.2941 | 24.449

# IfcWallStandardCase: Mur de base:fondations 60*45 (6)
In: Niveau rdc
Type - PredefinedType: STANDARD; Material: Maçonnerie - Voile BA 0.6 m
Type - Pset_WallCommon - IsExternal: yes
BaseQuantities - Height: 0.45 m; Width: 0.6 m
Pset_QuantityTakeOff - Reference: fondations 60*45; sets with these values: 2
Pset_WallCommon - LoadBearing: no; ExtendToStructure: no; Reference: fondations 60*45
Name (Mur de base:fondations 60*45:...) | Length (m) | GrossFootprintArea (m2) | GrossVolume (m3) = NetVolume (m3) | GrossSideArea (m2) = NetSideArea (m2)
376409 | 8.36 | 5.016 | 2.2572 | 3.762
376660 | 10.9 | 6.54 | 2.943 | 4.905
376714 | 7.76 | 4.656 | 2.0952 | 3.492
376788 | 10.3 | 6.18 | 2.781 | 4.635
398711 | 6.16257 | 3.69754 | 1.66389 | 2.77316
398897 | 7.16 | 4.296 | 1.9332 | 3.222

# IfcWindow: 1 Vantail - Droit:0.40m x 0.60m - Appui Béton (6)
Type - OperationType: SINGLE_PANEL; ParameterTakesPrecedence: no; Sizeable: no; Material: Fenêtre - Cadre, Fenêtre - Vitrage, Fenêtre - Appui, Fenêtre - Poignée
Type - Pset_WindowCommon - IsExternal: no
OverallHeight: 1.08 m; OverallWidth: 0.5 m; Material: Fenêtre - Poignée, Fenêtre - Appui, Fenêtre - Cadre, Fenêtre - Vitrage
Pset_QuantityTakeOff - Reference: 0.40m x 0.60m - Appui Béton
Pset_WindowCommon - Reference: 0.40m x 0.60m - Appui Béton
BaseQuantities - Height: 0.6 m; Width: 0.4 m; Area: 0.24 m2
Name (1 Vantail - Droit:0.40m x 0.60m - Appui Béton:...) | In
301706 | Niveau rdc | Pset_WindowCommon - IsExternal: yes
301790 | Niveau rdc
310493 | Niveau étage
310590 | Niveau étage
346839 | Niveau étage
349205 | Niveau étage

# IfcWindow: 1 Vantail - Droit:0.60m x 1.00m - Appui Béton 3 (4)
Type - OperationType: SINGLE_PANEL; ParameterTakesPrecedence: no; Sizeable: no; Material: Fenêtre - Cadre, Fenêtre - Vitrage, Fenêtre - Appui, Fenêtre - Poignée
Type - Pset_WindowCommon - IsExternal: no
OverallHeight: 1.13 m; OverallWidth: 0.7 m; Material: Fenêtre - Poignée, Fenêtre - Appui, Fenêtre - Vitrage, Fenêtre - Cadre
Pset_QuantityTakeOff - Reference: 0.60m x 1.00m - Appui Béton 3
Pset_WindowCommon - Reference: 0.60m x 1.00m - Appui Béton 3
BaseQuantities - Height: 1 m; Width: 0.6 m; Area: 0.6 m2
Name (1 Vantail - Droit:0.60m x 1.00m - Appui Béton 3:...) | In
319145 | Niveau rdc | Pset_WindowCommon - IsExternal: yes
319195 | Niveau rdc
319232 | Niveau rdc
332281 | Niveau comble

# IfcWindow: 1 Vantail - Droit:0.80m x 1.00m - Appui Béton 2 (2)
In: Niveau rdc
Type - OperationType: SINGLE_PANEL; ParameterTakesPrecedence: no; Sizeable: no; Material: Fenêtre - Poignée, Fenêtre - Appui, Fenêtre - Cadre(1), Fenêtre - Cadre, Fenêtre - Vitrage
Type - Pset_WindowCommon - IsExternal: no
OverallHeight: 1.13 m; OverallWidth: 0.9 m; Material: Fenêtre - Poignée, Fenêtre - Appui, Fenêtre - Vitrage, Fenêtre - Cadre(1), Fenêtre - Cadre
Pset_QuantityTakeOff - Reference: 0.80m x 1.00m - Appui Béton 2
Pset_WindowCommon - Reference: 0.80m x 1.00m - Appui Béton 2
BaseQuantities - Height: 1 m; Width: 0.8 m; Area: 0.8 m2
Name (1 Vantail - Droit:0.80m x 1.00m - Appui Béton 2:...)
319039 | Pset_WindowCommon - IsExternal: yes
319095

# IfcWindow: 2 Vantaux droits - Volets et petits bois:1.30m x 1.05m - Appui Béton (2)
In: Niveau rdc
Type - OperationType: DOUBLE_PANEL_VERTICAL; ParameterTakesPrecedence: no; Sizeable: no; Material: Volets - Bois, Fenêtre - Cadre(1), Fenêtre - Appui, Fenêtre - Cadre, Fenêtre - Vitrage, Fenêtre - Poignée
Type - Pset_WindowCommon - IsExternal: no
OverallHeight: 1.18 m; OverallWidth: 1.4 m; Material: Fenêtre - Poignée, Fenêtre - Appui, Fenêtre - Cadre(1), Fenêtre - Vitrage, Fenêtre - Cadre
Pset_QuantityTakeOff - Reference: 1.30m x 1.05m - Appui Béton
Pset_WindowCommon - Reference: 1.30m x 1.05m - Appui Béton
BaseQuantities - Height: 1.05 m; Width: 1.3 m; Area: 1.365 m2
Name (2 Vantaux droits - Volets et petits bois:1.30m x 1.05m - Appui Béton:...)
306936 | Pset_WindowCommon - IsExternal: yes
318979

# IfcWindow: 2 Vantaux droits - Volets et petits bois:1.40m x 1.35m - Appui Béton 2 (4)
In: Niveau étage
Type - OperationType: DOUBLE_PANEL_VERTICAL; ParameterTakesPrecedence: no; Sizeable: no; Material: Fenêtre - Vitrage, Fenêtre - Cadre, Volets - Bois, Fenêtre - Appui, Fenêtre - Cadre(1), Fenêtre - Poignée
Type - Pset_WindowCommon - IsExternal: no
OverallHeight: 1.48 m; OverallWidth: 1.5 m; Material: Fenêtre - Poignée, Fenêtre - Appui, Fenêtre - Cadre(1), Fenêtre - Vitrage, Fenêtre - Cadre
Pset_QuantityTakeOff - Reference: 1.40m x 1.35m - Appui Béton 2
Pset_WindowCommon - Reference: 1.40m x 1.35m - Appui Béton 2
BaseQuantities - Height: 1.35 m; Width: 1.4 m; Area: 1.89 m2
Name (2 Vantaux droits - Volets et petits bois:1.40m x 1.35m - Appui Béton 2:...)
310749 | Pset_WindowCommon - IsExternal: yes
310867
319583
319636

# IfcWindow: Fenêtre de toit:Fenêtre de toit (2)
In: Niveau comble
Type - ParameterTakesPrecedence: no; Sizeable: no; Material: <Unnamed>, Fenêtre de toit - Cadre
Type - Pset_WindowCommon - IsExternal: no; ThermalTransmittance: 3.6886 kg/K/s3
OverallHeight: 0.245 m; OverallWidth: 1.52 m; Material: <Unnamed>, Fenêtre de toit - Cadre, Fenêtre - Vitrage
Pset_QuantityTakeOff - Reference: Fenêtre de toit
Pset_WindowCommon - Reference: Fenêtre de toit
BaseQuantities - Height: 1.4 m; Width: 1.4 m; Area: 1.96 m2
Name (Fenêtre de toit:Fenêtre de toit:...)
327461 | Pset_WindowCommon - IsExternal: yes
327467

# IfcWindow: PF 2 Vantaux - Droits:1.50m x 2.15m, PF 2 Vantaux - Droits:1.50m x 2.15m:244606
In: Niveau étage
Type - OperationType: DOUBLE_PANEL_VERTICAL; ParameterTakesPrecedence: no; Sizeable: no; Material: Fenêtre - Cadre, Fenêtre - Vitrage, Fenêtre - Cadre(1), Fenêtre - Poignée, Fenêtre - Appui
Type - Pset_WindowCommon - IsExternal: no
OverallHeight: 2.265 m; OverallWidth: 2.6 m; Material: Fenêtre - Poignée, Fenêtre - Appui, Fenêtre - Cadre(1), Fenêtre - Vitrage, Fenêtre - Cadre
Pset_QuantityTakeOff - Reference: 1.50m x 2.15m
Pset_WindowCommon - IsExternal: yes; Reference: 1.50m x 2.15m
BaseQuantities - Height: 2.15 m; Width: 2.5 m; Area: 5.375 m2
